VERSION 5.7 ;
  NOWIREEXTENSIONATPIN ON ;
  DIVIDERCHAR "/" ;
  BUSBITCHARS "[]" ;
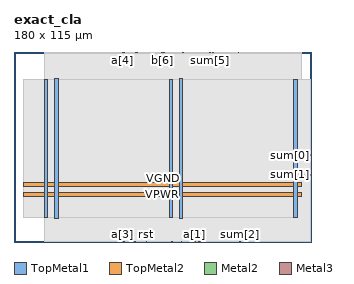
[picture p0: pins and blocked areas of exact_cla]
MACRO exact_cla
  CLASS BLOCK ;
  FOREIGN exact_cla ;
  ORIGIN 0.000 0.000 ;
  SIZE 180.000 BY 115.000 ;
  PIN VGND
    DIRECTION INOUT ;
    USE GROUND ;
    PORT
      LAYER TopMetal1 ;
        RECT 24.460 14.490 26.660 98.910 ;
    END
    PORT
      LAYER TopMetal1 ;
        RECT 100.060 14.490 102.260 98.910 ;
    END
    PORT
      LAYER TopMetal2 ;
        RECT 5.760 33.820 174.240 36.020 ;
    END
  END VGND
  PIN VPWR
    DIRECTION INOUT ;
    USE POWER ;
    PORT
      LAYER TopMetal1 ;
        RECT 18.260 14.900 20.460 98.500 ;
    END
    PORT
      LAYER TopMetal1 ;
        RECT 93.860 14.900 96.060 98.500 ;
    END
    PORT
      LAYER TopMetal1 ;
        RECT 169.460 14.900 171.660 98.500 ;
    END
    PORT
      LAYER TopMetal2 ;
        RECT 5.760 27.620 174.240 29.820 ;
    END
  END VPWR
  PIN a[0]
    DIRECTION INPUT ;
    USE SIGNAL ;
    ANTENNAGATEAREA 0.180700 ;
    PORT
      LAYER Metal2 ;
        RECT 111.640 0.000 112.040 0.400 ;
    END
  END a[0]
  PIN a[1]
    DIRECTION INPUT ;
    USE SIGNAL ;
    ANTENNAGATEAREA 0.180700 ;
    PORT
      LAYER Metal2 ;
        RECT 108.760 0.000 109.160 0.400 ;
    END
  END a[1]
  PIN a[2]
    DIRECTION INPUT ;
    USE SIGNAL ;
    ANTENNAGATEAREA 0.180700 ;
    PORT
      LAYER Metal2 ;
        RECT 73.240 0.000 73.640 0.400 ;
    END
  END a[2]
  PIN a[3]
    DIRECTION INPUT ;
    USE SIGNAL ;
    ANTENNAGATEAREA 0.180700 ;
    PORT
      LAYER Metal2 ;
        RECT 65.560 0.000 65.960 0.400 ;
    END
  END a[3]
  PIN a[4]
    DIRECTION INPUT ;
    USE SIGNAL ;
    ANTENNAGATEAREA 0.180700 ;
    PORT
      LAYER Metal2 ;
        RECT 65.560 114.600 65.960 115.000 ;
    END
  END a[4]
  PIN a[5]
    DIRECTION INPUT ;
    USE SIGNAL ;
    ANTENNAGATEAREA 0.180700 ;
    PORT
      LAYER Metal2 ;
        RECT 73.240 114.600 73.640 115.000 ;
    END
  END a[5]
  PIN a[6]
    DIRECTION INPUT ;
    USE SIGNAL ;
    ANTENNAGATEAREA 0.180700 ;
    PORT
      LAYER Metal2 ;
        RECT 90.520 114.600 90.920 115.000 ;
    END
  END a[6]
  PIN b[0]
    DIRECTION INPUT ;
    USE SIGNAL ;
    ANTENNAGATEAREA 0.180700 ;
    PORT
      LAYER Metal2 ;
        RECT 112.600 0.000 113.000 0.400 ;
    END
  END b[0]
  PIN b[1]
    DIRECTION INPUT ;
    USE SIGNAL ;
    ANTENNAGATEAREA 0.180700 ;
    PORT
      LAYER Metal2 ;
        RECT 109.720 0.000 110.120 0.400 ;
    END
  END b[1]
  PIN b[2]
    DIRECTION INPUT ;
    USE SIGNAL ;
    ANTENNAGATEAREA 0.180700 ;
    PORT
      LAYER Metal2 ;
        RECT 72.280 0.000 72.680 0.400 ;
    END
  END b[2]
  PIN b[3]
    DIRECTION INPUT ;
    USE SIGNAL ;
    ANTENNAGATEAREA 0.180700 ;
    PORT
      LAYER Metal2 ;
        RECT 66.520 0.000 66.920 0.400 ;
    END
  END b[3]
  PIN b[4]
    DIRECTION INPUT ;
    USE SIGNAL ;
    ANTENNAGATEAREA 0.180700 ;
    PORT
      LAYER Metal2 ;
        RECT 66.520 114.600 66.920 115.000 ;
    END
  END b[4]
  PIN b[5]
    DIRECTION INPUT ;
    USE SIGNAL ;
    ANTENNAGATEAREA 0.180700 ;
    PORT
      LAYER Metal2 ;
        RECT 74.200 114.600 74.600 115.000 ;
    END
  END b[5]
  PIN b[6]
    DIRECTION INPUT ;
    USE SIGNAL ;
    ANTENNAGATEAREA 0.180700 ;
    PORT
      LAYER Metal2 ;
        RECT 89.560 114.600 89.960 115.000 ;
    END
  END b[6]
  PIN clk
    DIRECTION INPUT ;
    USE SIGNAL ;
    ANTENNAGATEAREA 1.450800 ;
    PORT
      LAYER Metal2 ;
        RECT 95.320 0.000 95.720 0.400 ;
    END
  END clk
  PIN rst
    DIRECTION INPUT ;
    USE SIGNAL ;
    ANTENNAGATEAREA 0.180700 ;
    PORT
      LAYER Metal2 ;
        RECT 79.960 0.000 80.360 0.400 ;
    END
  END rst
  PIN sum[0]
    DIRECTION OUTPUT ;
    USE SIGNAL ;
    ANTENNADIFFAREA 0.708600 ;
    PORT
      LAYER Metal3 ;
        RECT 179.600 52.300 180.000 52.700 ;
    END
  END sum[0]
  PIN sum[1]
    DIRECTION OUTPUT ;
    USE SIGNAL ;
    ANTENNADIFFAREA 0.708600 ;
    PORT
      LAYER Metal3 ;
        RECT 179.600 40.540 180.000 40.940 ;
    END
  END sum[1]
  PIN sum[2]
    DIRECTION OUTPUT ;
    USE SIGNAL ;
    ANTENNADIFFAREA 0.708600 ;
    PORT
      LAYER Metal2 ;
        RECT 136.600 0.000 137.000 0.400 ;
    END
  END sum[2]
  PIN sum[3]
    DIRECTION OUTPUT ;
    USE SIGNAL ;
    ANTENNADIFFAREA 0.708600 ;
    PORT
      LAYER Metal2 ;
        RECT 101.080 0.000 101.480 0.400 ;
    END
  END sum[3]
  PIN sum[4]
    DIRECTION OUTPUT ;
    USE SIGNAL ;
    ANTENNADIFFAREA 0.708600 ;
    PORT
      LAYER Metal2 ;
        RECT 102.040 114.600 102.440 115.000 ;
    END
  END sum[4]
  PIN sum[5]
    DIRECTION OUTPUT ;
    USE SIGNAL ;
    ANTENNADIFFAREA 0.708600 ;
    PORT
      LAYER Metal2 ;
        RECT 118.360 114.600 118.760 115.000 ;
    END
  END sum[5]
  PIN sum[6]
    DIRECTION OUTPUT ;
    USE SIGNAL ;
    ANTENNADIFFAREA 0.708600 ;
    PORT
      LAYER Metal2 ;
        RECT 135.640 114.600 136.040 115.000 ;
    END
  END sum[6]
  PIN sum[7]
    DIRECTION OUTPUT ;
    USE SIGNAL ;
    ANTENNADIFFAREA 0.708600 ;
    PORT
      LAYER Metal2 ;
        RECT 120.280 114.600 120.680 115.000 ;
    END
  END sum[7]
  OBS
      LAYER GatPoly ;
        RECT 5.760 14.970 174.240 98.430 ;
      LAYER Metal1 ;
        RECT 5.760 14.900 174.240 98.500 ;
      LAYER Metal2 ;
        RECT 18.440 114.390 65.350 114.600 ;
        RECT 66.170 114.390 66.310 114.600 ;
        RECT 67.130 114.390 73.030 114.600 ;
        RECT 73.850 114.390 73.990 114.600 ;
        RECT 74.810 114.390 89.350 114.600 ;
        RECT 90.170 114.390 90.310 114.600 ;
        RECT 91.130 114.390 101.830 114.600 ;
        RECT 102.650 114.390 118.150 114.600 ;
        RECT 118.970 114.390 120.070 114.600 ;
        RECT 120.890 114.390 135.430 114.600 ;
        RECT 136.250 114.390 173.865 114.600 ;
        RECT 18.440 0.610 173.865 114.390 ;
        RECT 18.440 0.275 65.350 0.610 ;
        RECT 66.170 0.275 66.310 0.610 ;
        RECT 67.130 0.275 72.070 0.610 ;
        RECT 72.890 0.275 73.030 0.610 ;
        RECT 73.850 0.275 79.750 0.610 ;
        RECT 80.570 0.275 95.110 0.610 ;
        RECT 95.930 0.275 100.870 0.610 ;
        RECT 101.690 0.275 108.550 0.610 ;
        RECT 109.370 0.275 109.510 0.610 ;
        RECT 110.330 0.275 111.430 0.610 ;
        RECT 112.250 0.275 112.390 0.610 ;
        RECT 113.210 0.275 136.390 0.610 ;
        RECT 137.210 0.275 173.865 0.610 ;
      LAYER Metal3 ;
        RECT 18.395 52.910 179.600 98.380 ;
        RECT 18.395 52.090 179.390 52.910 ;
        RECT 18.395 41.150 179.600 52.090 ;
        RECT 18.395 40.330 179.390 41.150 ;
        RECT 18.395 0.320 179.600 40.330 ;
      LAYER Metal4 ;
        RECT 18.440 14.975 171.480 98.425 ;
      LAYER Metal5 ;
        RECT 18.395 14.810 171.525 98.590 ;
  END
END exact_cla
END LIBRARY

